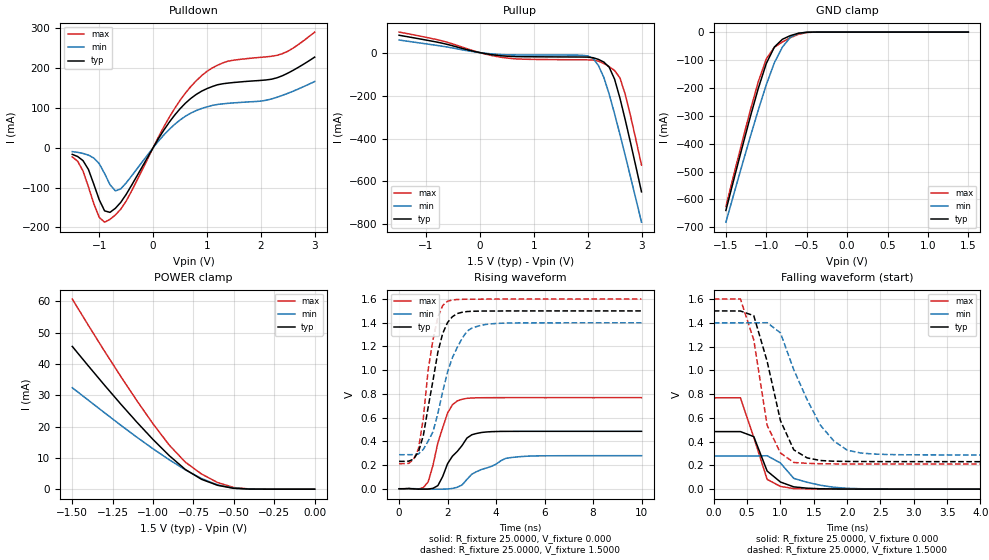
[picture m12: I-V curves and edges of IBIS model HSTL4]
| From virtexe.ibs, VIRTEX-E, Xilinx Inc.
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|   Model HSTL4
[Model]   HSTL4
Model_type   I/O
Polarity   Non-Inverting
Enable   Active-Low
Vinl =   0.800V
Vinh =   1.000V
Vmeas =   0.9000V
Cref =  20.0000pF
Rref =  25.0000
Vref =   1.5000V
C_comp   5.0000pF   4.0000pF   6.0000pF
[Temperature Range]   25.0000   100.0000   0.000
[Voltage Range]   1.5000V   1.4000V   1.6000V
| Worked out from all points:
|   slope of the pulldown table from 0 to 0.225 V, typ, clamps not added: 4.56 ohm
|   slope of the pullup table from 0 to 0.225 V, typ, clamps not added: 23.5 ohm
|   GND clamp passes 1 mA (typ) near -0.51 V on its own axis
|   POWER clamp passes 1 mA (typ) near -0.58 V on its own axis
|   rising waveform, R_fixture 25.0000, V_fixture 0.000: 20-80 % time 889ps typ, 1.41ns min, 626ps max; typ from 0 V to 0.484 V
|   rising waveform, R_fixture 25.0000, V_fixture 1.5000: 20-80 % time 688ps typ, 928ps min, 548ps max; typ from 0.231 V to 1.5 V
|   falling waveform, R_fixture 25.0000, V_fixture 0.000: 20-80 % time 283ps typ, 427ps min, 267ps max; typ from 0.484 V to 0 V
|   falling waveform, R_fixture 25.0000, V_fixture 1.5000: 20-80 % time 363ps typ, 554ps min, 280ps max; typ from 1.5 V to 0.231 V
[Pulldown]
| voltage   I(typ)   I(min)   I(max)
-1.5V     -16.6mA    -9.7mA     -22.8mA
-1.3V     -32.4mA    -14.3mA    -58.4mA
-1.2V     -54.6mA    -18.5mA    -98.4mA
-1V       -130.6mA   -39.9mA    -174.9mA
-900mV    -158.6mA   -64.8mA    -187.1mA
-700mV    -152.2mA   -108.4mA   -168.9mA
-600mV    -137.2mA   -103.4mA   -154.3mA
300mV     64.1mA     46.22mA    76.58mA
900mV     142.2mA    98.61mA    181.1mA
1.4V      162.7mA    111.8mA    218mA
2.3V      175.9mA    127mA      232.4mA
3V        227.9mA    166.6mA    290.8mA
[Pullup]
| voltage   I(typ)   I(min)   I(max)
-1.5V     80.99mA    58.81mA    95.66mA
-700mV    43.92mA    29.88mA    54.7mA
400mV     -14.75mA   -8.945mA   -21.71mA
1.9V      -20.46mA   -12.26mA   -33.54mA
2.1V      -23.68mA   -26.88mA   -34.7mA
2.2V      -31.41mA   -60.03mA   -39.61mA
2.3V      -43.82mA   -115mA     -50.52mA
2.4V      -67.75mA   -193.4mA   -65.34mA
2.5V      -123.4mA   -284.7mA   -83.26mA
2.6V      -212.2mA   -381.6mA   -117.7mA
2.7V      -315.2mA   -481.5mA   -196.1mA
3V        -648.4mA   -789.7mA   -524mA
[GND_clamp]
| voltage   I(typ)   I(min)   I(max)
-1.5V     -639.4mA   -681.4mA   -625.3mA
-1.3V     -414.8mA   -476.9mA   -394mA
-1.2V     -306mA     -377mA     -282.7mA
-1.1V     -202.5mA   -280mA     -178.7mA
-1V       -112.5mA   -188.5mA   -95.97mA
-900mV    -53.49mA   -109.7mA   -54.51mA
-800mV    -25.66mA   -53.59mA   -35.12mA
-700mV    -12.43mA   -17.88mA   -19.81mA
-600mV    -3.981mA   -4.201mA   -7.863mA
-500mV    -601.5uA   -800.2uA   -1.508mA
-400mV    -51.04uA   -119.3uA   -124.3uA
1.5V      8.586nA    31.4nA     8.324nA
[POWER_clamp]
| voltage   I(typ)   I(min)   I(max)
-1.5V     45.61mA    32.41mA    60.74mA
-1.3V     33.2mA     24.4mA     44.06mA
-1.1V     21.39mA    16.59mA    28.25mA
-1V       15.85mA    12.89mA    20.86mA
-900mV    10.72mA    9.386mA    14.08mA
-800mV    6.271mA    6.174mA    8.616mA
-700mV    3.136mA    3.398mA    4.838mA
-600mV    1.222mA    1.343mA    2.099mA
-500mV    258.2uA    323.8uA    517.7uA
-400mV    22.21uA    43.58uA    48.44uA
0V        8.586nA    20.17nA    9.284nA
[Ramp]
| variable   typ   min   max
dV/dt_r   0.2907/0.8886n   0.1673/1.3792n   0.4611/0.5932n
dV/dt_f   0.7612/0.3033n   0.6676/0.4814n   0.8330/0.2405n
R_load = 25.0000
[Rising Waveform]
R_fixture = 25.0000
V_fixture = 0.000
| time   V(typ)   V(min)   V(max)
0s        0V         0V         0V
800ps     -3.415mV   -321.3uV   -2.634mV
1.2ns     -2.71mV    -3.271mV   58.03mV
1.4ns     3.624mV    -3.341mV   199.6mV
1.6ns     26.55mV    -3.482mV   387.7mV
2ns       211.4mV    -1.966mV   638.8mV
2.4ns     314.6mV    12.65mV    740.9mV
3ns       455.5mV    123mV      765.8mV
4.4ns     484mV      256.1mV    768.5mV
10ns      484.5mV    278.9mV    768.5mV
[Rising Waveform]
R_fixture = 25.0000
V_fixture = 1.5000
V_fixture_min = 1.4000
V_fixture_max = 1.6000
| time   V(typ)   V(min)   V(max)
0s        231.2mV    287.2mV    211.7mV
800ps     312.2mV    293.9mV    337.8mV
1ns       448.7mV    332.4mV    593.3mV
1.2ns     688.7mV    402.6mV    1.003V
1.4ns     915.3mV    481.2mV    1.26V
1.6ns     1.153V     635.5mV    1.448V
2ns       1.403V     985.7mV    1.582V
2.8ns     1.495V     1.328V     1.599V
3.4ns     1.499V     1.379V     1.599V
10ns      1.5V       1.4V       1.6V
[Falling Waveform]
R_fixture = 25.0000
V_fixture = 0.000
| time   V(typ)   V(min)   V(max)
0s        484.5mV    278.9mV    768.5mV
400ps     484.5mV    278.9mV    769mV
600ps     442.5mV    278.7mV    435.4mV
800ps     152.9mV    281.6mV    82.75mV
1ns       60.15mV    220.4mV    23.04mV
1.2ns     19.39mV    90.71mV    5.026mV
1.6ns     3.173mV    32.94mV    1.264mV
1.8ns     1.741mV    16.2mV     762.5uV
2.2ns     721.2uV    3.814mV    382uV
10ns      32.67uV    63.74uV    28uV
[Falling Waveform]
R_fixture = 25.0000
V_fixture = 1.5000
V_fixture_min = 1.4000
V_fixture_max = 1.6000
| time   V(typ)   V(min)   V(max)
0s        1.5V       1.4V       1.6V
400ps     1.5V       1.4V       1.6V
600ps     1.46V      1.4V       1.256V
800ps     1.077V     1.401V     538.1mV
1ns       577.3mV    1.316V     304.8mV
1.2ns     331mV      1.005V     224.6mV
1.6ns     241.1mV    538mV      214mV
1.8ns     235.2mV    406.4mV    212.9mV
2.2ns     232.6mV    304.5mV    212.2mV
10ns      231.3mV    287.3mV    211.7mV
